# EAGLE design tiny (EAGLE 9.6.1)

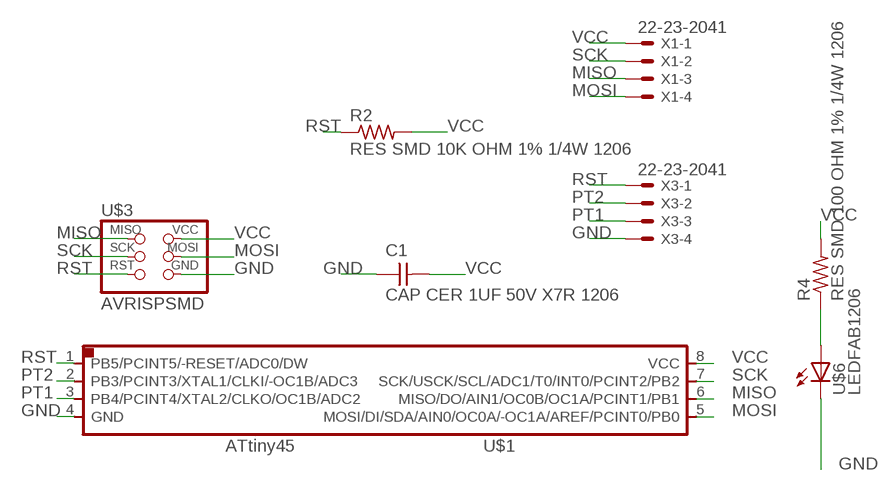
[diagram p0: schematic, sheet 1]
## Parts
C1  CAP CER 1UF 50V X7R 1206  CAP-UNPOLARIZEDFAB  [C1206FAB]
R2  RES SMD 10K OHM 1% 1/4W 1206  RES-US1206FAB  [R1206FAB]
R4  RES SMD 100 OHM 1% 1/4W 1206  RES-US1206FAB  [R1206FAB]
U$1  ATTINY45SI  [SOIC8]
U$3  AVRISPSMD  [2X03SMD]
U$6  LEDFAB1206  [LED1206FAB]
X1  22-23-2041  [22-23-2041]
X3  22-23-2041  [22-23-2041]

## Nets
GND: C1.1 U$1.4(GND) U$3.6(GND) U$6.2(C) X3.4
MISO: U$1.6(MISO/DO/AIN1/OC0B/OC1A/PCINT1/PB1) U$3.1(MISO) X1.3
MOSI: U$1.5(MOSI/DI/SDA/AIN0/OC0A/-OC1A/AREF/PCINT0/PB0) U$3.4(MOSI) X1.4
PB2: R4.1 U$6.1(A)
PT1: U$1.3(PB4/PCINT4/XTAL2/CLKO/OC1B/ADC2) X3.3
PT2: U$1.2(PB3/PCINT3/XTAL1/CLKI/-OC1B/ADC3) X3.2
RST: R2.1 U$1.1(PB5/PCINT5/-RESET/ADC0/DW) U$3.5(RST) X3.1
SCK: U$1.7(SCK/USCK/SCL/ADC1/T0/INT0/PCINT2/PB2) U$3.3(SCK) X1.2
VCC: C1.2 R2.2 R4.2 U$1.8(VCC) U$3.2(VCC) X1.1

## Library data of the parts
C1 = fab:CAP-UNPOLARIZED
R2 R4 = fab:RES-US: Resistor (US Symbol)
U$1 = fab:ATTINY45
U$3 = fab:AVRISP
U$6 = fab:LED: LED
X1 X3 = con-molex:22-23-2041: .100" (2.54mm) Center Header - 4 Pin; MF: MOLEX; MPN: 22-23-2041; OC_FARNELL: 1462920; OC_NEWARK: 38C0355

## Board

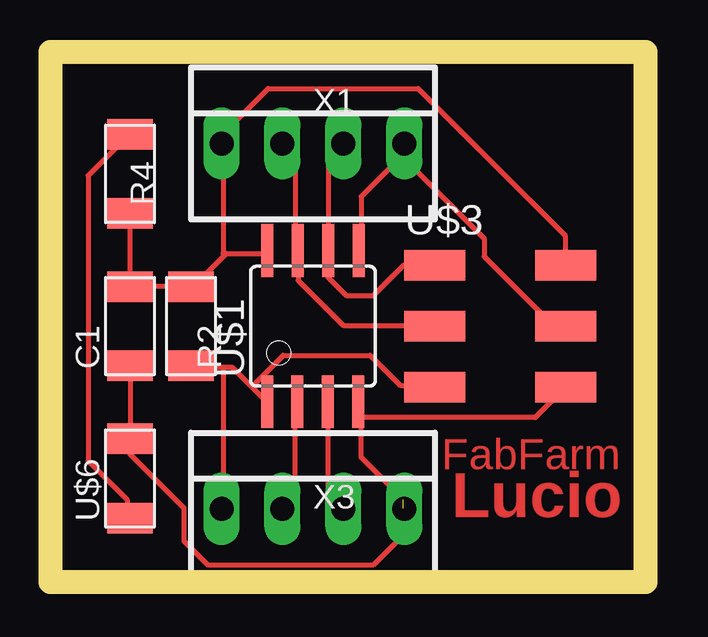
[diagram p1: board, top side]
Size 24.49 x 21.56 mm. Coordinates in mm from the lower left corner, seen from the top.
Outline: 0,0 24.49,0 24.49,21.56 0,21.56 0,0
Copper layers (1*16): Top 0.035mm / dielectric 1.5mm / Bottom 0.035mm
Design rules "default *": minimum track width 0.2mm, minimum drill 0.35mm, track to track 25mil, track to pad 25mil, pad to pad 25mil, via to via 25mil, smd to smd 25mil, copper to edge 10mil, drill to drill 6mil, minimum pad ring 10mil, minimum via ring 8mil, stop-mask expansion 4mil, vias tented up to drill 0mil, thermal gap 10mil
Milling: 4 lines

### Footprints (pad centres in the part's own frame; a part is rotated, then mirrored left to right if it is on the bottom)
C1206FAB = smd 1.27 x 1.905: 1 -1.651,0; 2 1.651,0
R1206FAB = smd 1.27 x 1.905: 1 -1.651,0; 2 1.651,0
SOIC8 = smd 0.5 x 2.2: 1 -1.905,-3.154; 2 -0.645,-3.154; 3 0.625,-3.154; 4 1.895,-3.154; 5 1.905,3.154; 6 0.635,3.154; 7 -0.635,3.154; 8 -1.905,3.154
2X03SMD = smd 2.54 x 1.27: 1 -2.54,2.54; 2 2.92,2.54; 3 -2.54,0; 4 2.92,0; 5 -2.54,-2.54; 6 2.92,-2.54
LED1206FAB = smd 1.27 x 1.905: 1 -1.651,0; 2 1.651,0
22-23-2041 = drill 1 long: 1 -3.81,0; 2 -1.27,0; 3 1.27,0; 4 3.81,0

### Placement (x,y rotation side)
C1  2.92,10.46 90 top
R2  5.46,10.46 90 top
R4  2.92,16.81 270 top
U$1  10.54,10.46 0 top
U$3  18.16,10.46 0 top
U$6  2.92,4.11 90 top
X1  10.54,18.08 0 top
X3  10.54,2.84 0 top

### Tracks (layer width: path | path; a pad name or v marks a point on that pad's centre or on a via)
GND  (1 unrouted)
  Top 0.2: C1.1 2.92,8.74 2.92,5.87 U$6.2 2.92,5.74 2.92,5.12 5.17,2.87 5.17,1.49 6.17,0.49 13.05,0.49 14.43,1.87 X3.4 | 12.55,6.65 12.55,4.99 14.3,3.24 | 12.55,6.65 12.55,7.24 U$1.4 | 14.3,2.87 X3.4 | 14.66,3.81 14.35,3.5 X3.4 | U$3.6 19.81,6.65 12.55,6.65
MISO
  Top 0.2: X1.3 11.8,17.99 11.18,17.37 U$1.6 11.18,12.49 11.93,11.74 13.05,11.74 14.3,12.99 15.55,12.99 U$3.1
MOSI
  Top 0.2: U$1.5 12.55,13.62 12.55,15.87 14.3,17.62 14.3,17.99 X1.4 14.3,17.49 17.68,14.12 17.68,13.37 20.55,10.49 21.05,10.49 U$3.4
PB2
  Top 0.2: U$6.1 2.8,2.47 2.8,3.22 1.17,4.85 1.17,16.74 2.8,18.37 R4.1
PT1
  Top 0.2: U$1.3 11.18,7.24 11.18,3.49 11.8,2.87 X3.3
PT2
  Top 0.2: U$1.2 9.8,7.24 9.8,3.37 9.3,2.87 X3.2
RST
  Top 0.2: 6.8,8.74 7.17,8.74 7.99,7.93 | 6.8,8.74 5.55,8.74 R2.1 | 7.99,7.93 8.55,7.37 U$1.1 | 7.99,7.93 9.3,9.24 12.93,9.24 14.18,7.99 15.55,7.99 U$3.5 | 6.8,8.74 6.8,2.87 X3.1
SCK
  Top 0.2: X1.2 9.3,17.99 9.8,17.49 9.8,13.62 U$1.7 9.93,13.49 9.93,12.37 11.8,10.49 15.55,10.49 U$3.3
VCC
  Top 0.2: C1.2 5.42,12.12 R2.2 5.55,12.12 6.86,13.43 | C1.2 2.92,15.12 R4.2 | C1.2 | 6.86,13.43 6.92,13.49 8.55,13.49 U$1.8 | U$3.2 21.05,13.12 21.05,14.24 14.93,20.37 8.68,20.37 6.8,18.49 6.8,18.12 X1.1 6.8,17.99 6.8,13.49 6.86,13.43

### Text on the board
Top: FabFarm | Lucio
